VERSION 5.7 ;
  NOWIREEXTENSIONATPIN ON ;
  DIVIDERCHAR "/" ;
  BUSBITCHARS "[]" ;
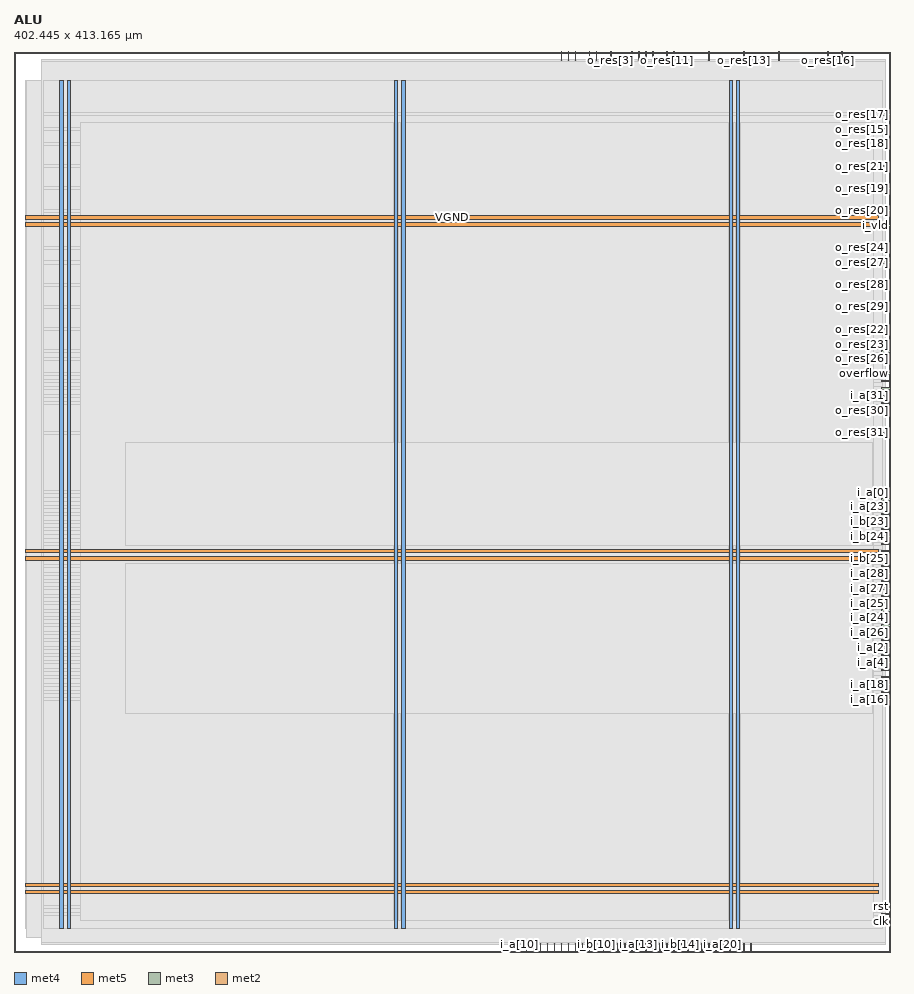
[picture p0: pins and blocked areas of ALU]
MACRO ALU
  CLASS BLOCK ;
  FOREIGN ALU ;
  ORIGIN 0.000 0.000 ;
  SIZE 402.445 BY 413.165 ;
  PIN VGND
    DIRECTION INOUT ;
    USE GROUND ;
    PORT
      LAYER met4 ;
        RECT 24.340 10.640 25.940 400.080 ;
    END
    PORT
      LAYER met4 ;
        RECT 177.940 10.640 179.540 400.080 ;
    END
    PORT
      LAYER met4 ;
        RECT 331.540 10.640 333.140 400.080 ;
    END
    PORT
      LAYER met5 ;
        RECT 5.280 30.030 396.760 31.630 ;
    END
    PORT
      LAYER met5 ;
        RECT 5.280 183.210 396.760 184.810 ;
    END
    PORT
      LAYER met5 ;
        RECT 5.280 336.390 396.760 337.990 ;
    END
  END VGND
  PIN VPWR
    DIRECTION INOUT ;
    USE POWER ;
    PORT
      LAYER met4 ;
        RECT 21.040 10.640 22.640 400.080 ;
    END
    PORT
      LAYER met4 ;
        RECT 174.640 10.640 176.240 400.080 ;
    END
    PORT
      LAYER met4 ;
        RECT 328.240 10.640 329.840 400.080 ;
    END
    PORT
      LAYER met5 ;
        RECT 5.280 26.730 396.760 28.330 ;
    END
    PORT
      LAYER met5 ;
        RECT 5.280 179.910 396.760 181.510 ;
    END
    PORT
      LAYER met5 ;
        RECT 5.280 333.090 396.760 334.690 ;
    END
  END VPWR
  PIN clk
    DIRECTION INPUT ;
    USE SIGNAL ;
    ANTENNAGATEAREA 0.852000 ;
    PORT
      LAYER met3 ;
        RECT 398.445 17.040 402.445 17.640 ;
    END
  END clk
  PIN i_a[0]
    DIRECTION INPUT ;
    USE SIGNAL ;
    ANTENNAGATEAREA 0.196500 ;
    PORT
      LAYER met3 ;
        RECT 398.445 210.840 402.445 211.440 ;
    END
  END i_a[0]
  PIN i_a[10]
    DIRECTION INPUT ;
    USE SIGNAL ;
    ANTENNAGATEAREA 0.196500 ;
    PORT
      LAYER met2 ;
        RECT 231.930 0.000 232.210 4.000 ;
    END
  END i_a[10]
  PIN i_a[11]
    DIRECTION INPUT ;
    USE SIGNAL ;
    ANTENNAGATEAREA 0.196500 ;
    PORT
      LAYER met2 ;
        RECT 251.250 0.000 251.530 4.000 ;
    END
  END i_a[11]
  PIN i_a[12]
    DIRECTION INPUT ;
    USE SIGNAL ;
    ANTENNAGATEAREA 0.196500 ;
    PORT
      LAYER met2 ;
        RECT 283.450 0.000 283.730 4.000 ;
    END
  END i_a[12]
  PIN i_a[13]
    DIRECTION INPUT ;
    USE SIGNAL ;
    ANTENNAGATEAREA 0.196500 ;
    PORT
      LAYER met2 ;
        RECT 286.670 0.000 286.950 4.000 ;
    END
  END i_a[13]
  PIN i_a[14]
    DIRECTION INPUT ;
    USE SIGNAL ;
    ANTENNAGATEAREA 0.196500 ;
    PORT
      LAYER met2 ;
        RECT 293.110 0.000 293.390 4.000 ;
    END
  END i_a[14]
  PIN i_a[15]
    DIRECTION INPUT ;
    USE SIGNAL ;
    ANTENNAGATEAREA 0.196500 ;
    PORT
      LAYER met2 ;
        RECT 289.890 0.000 290.170 4.000 ;
    END
  END i_a[15]
  PIN i_a[16]
    DIRECTION INPUT ;
    USE SIGNAL ;
    ANTENNAGATEAREA 0.196500 ;
    PORT
      LAYER met3 ;
        RECT 398.445 115.640 402.445 116.240 ;
    END
  END i_a[16]
  PIN i_a[17]
    DIRECTION INPUT ;
    USE SIGNAL ;
    ANTENNAGATEAREA 0.196500 ;
    PORT
      LAYER met3 ;
        RECT 398.445 132.640 402.445 133.240 ;
    END
  END i_a[17]
  PIN i_a[18]
    DIRECTION INPUT ;
    USE SIGNAL ;
    ANTENNAGATEAREA 0.196500 ;
    PORT
      LAYER met3 ;
        RECT 398.445 119.040 402.445 119.640 ;
    END
  END i_a[18]
  PIN i_a[19]
    DIRECTION INPUT ;
    USE SIGNAL ;
    ANTENNAGATEAREA 0.196500 ;
    PORT
      LAYER met3 ;
        RECT 398.445 122.440 402.445 123.040 ;
    END
  END i_a[19]
  PIN i_a[1]
    DIRECTION INPUT ;
    USE SIGNAL ;
    ANTENNAGATEAREA 0.196500 ;
    PORT
      LAYER met3 ;
        RECT 398.445 149.640 402.445 150.240 ;
    END
  END i_a[1]
  PIN i_a[20]
    DIRECTION INPUT ;
    USE SIGNAL ;
    ANTENNAGATEAREA 0.196500 ;
    PORT
      LAYER met2 ;
        RECT 325.310 0.000 325.590 4.000 ;
    END
  END i_a[20]
  PIN i_a[21]
    DIRECTION INPUT ;
    USE SIGNAL ;
    ANTENNAGATEAREA 0.196500 ;
    PORT
      LAYER met2 ;
        RECT 322.090 0.000 322.370 4.000 ;
    END
  END i_a[21]
  PIN i_a[22]
    DIRECTION INPUT ;
    USE SIGNAL ;
    ANTENNAGATEAREA 0.196500 ;
    PORT
      LAYER met2 ;
        RECT 312.430 0.000 312.710 4.000 ;
    END
  END i_a[22]
  PIN i_a[23]
    DIRECTION INPUT ;
    USE SIGNAL ;
    ANTENNAGATEAREA 0.196500 ;
    PORT
      LAYER met3 ;
        RECT 398.445 204.040 402.445 204.640 ;
    END
  END i_a[23]
  PIN i_a[24]
    DIRECTION INPUT ;
    USE SIGNAL ;
    ANTENNAGATEAREA 0.196500 ;
    PORT
      LAYER met3 ;
        RECT 398.445 153.040 402.445 153.640 ;
    END
  END i_a[24]
  PIN i_a[25]
    DIRECTION INPUT ;
    USE SIGNAL ;
    ANTENNAGATEAREA 0.196500 ;
    PORT
      LAYER met3 ;
        RECT 398.445 156.440 402.445 157.040 ;
    END
  END i_a[25]
  PIN i_a[26]
    DIRECTION INPUT ;
    USE SIGNAL ;
    ANTENNAGATEAREA 0.196500 ;
    PORT
      LAYER met3 ;
        RECT 398.445 146.240 402.445 146.840 ;
    END
  END i_a[26]
  PIN i_a[27]
    DIRECTION INPUT ;
    USE SIGNAL ;
    ANTENNAGATEAREA 0.196500 ;
    PORT
      LAYER met3 ;
        RECT 398.445 163.240 402.445 163.840 ;
    END
  END i_a[27]
  PIN i_a[28]
    DIRECTION INPUT ;
    USE SIGNAL ;
    ANTENNAGATEAREA 0.196500 ;
    PORT
      LAYER met3 ;
        RECT 398.445 173.440 402.445 174.040 ;
    END
  END i_a[28]
  PIN i_a[29]
    DIRECTION INPUT ;
    USE SIGNAL ;
    ANTENNAGATEAREA 0.196500 ;
    PORT
      LAYER met3 ;
        RECT 398.445 207.440 402.445 208.040 ;
    END
  END i_a[29]
  PIN i_a[2]
    DIRECTION INPUT ;
    USE SIGNAL ;
    ANTENNAGATEAREA 0.196500 ;
    PORT
      LAYER met3 ;
        RECT 398.445 142.840 402.445 143.440 ;
    END
  END i_a[2]
  PIN i_a[30]
    DIRECTION INPUT ;
    USE SIGNAL ;
    ANTENNAGATEAREA 0.196500 ;
    PORT
      LAYER met3 ;
        RECT 398.445 170.040 402.445 170.640 ;
    END
  END i_a[30]
  PIN i_a[31]
    DIRECTION INPUT ;
    USE SIGNAL ;
    ANTENNAGATEAREA 0.196500 ;
    PORT
      LAYER met3 ;
        RECT 398.445 255.040 402.445 255.640 ;
    END
  END i_a[31]
  PIN i_a[3]
    DIRECTION INPUT ;
    USE SIGNAL ;
    ANTENNAGATEAREA 0.196500 ;
    PORT
      LAYER met3 ;
        RECT 398.445 159.840 402.445 160.440 ;
    END
  END i_a[3]
  PIN i_a[4]
    DIRECTION INPUT ;
    USE SIGNAL ;
    ANTENNAGATEAREA 0.196500 ;
    PORT
      LAYER met3 ;
        RECT 398.445 136.040 402.445 136.640 ;
    END
  END i_a[4]
  PIN i_a[5]
    DIRECTION INPUT ;
    USE SIGNAL ;
    ANTENNAGATEAREA 0.196500 ;
    PORT
      LAYER met3 ;
        RECT 398.445 139.440 402.445 140.040 ;
    END
  END i_a[5]
  PIN i_a[6]
    DIRECTION INPUT ;
    USE SIGNAL ;
    ANTENNAGATEAREA 0.196500 ;
    PORT
      LAYER met3 ;
        RECT 398.445 125.840 402.445 126.440 ;
    END
  END i_a[6]
  PIN i_a[7]
    DIRECTION INPUT ;
    USE SIGNAL ;
    ANTENNAGATEAREA 0.196500 ;
    PORT
      LAYER met3 ;
        RECT 398.445 129.240 402.445 129.840 ;
    END
  END i_a[7]
  PIN i_a[8]
    DIRECTION INPUT ;
    USE SIGNAL ;
    ANTENNAGATEAREA 0.196500 ;
    PORT
      LAYER met2 ;
        RECT 244.810 0.000 245.090 4.000 ;
    END
  END i_a[8]
  PIN i_a[9]
    DIRECTION INPUT ;
    USE SIGNAL ;
    ANTENNAGATEAREA 0.196500 ;
    PORT
      LAYER met2 ;
        RECT 238.370 0.000 238.650 4.000 ;
    END
  END i_a[9]
  PIN i_b[0]
    DIRECTION INPUT ;
    USE SIGNAL ;
    ANTENNAGATEAREA 0.196500 ;
    PORT
      LAYER met2 ;
        RECT 257.690 0.000 257.970 4.000 ;
    END
  END i_b[0]
  PIN i_b[10]
    DIRECTION INPUT ;
    USE SIGNAL ;
    ANTENNAGATEAREA 0.196500 ;
    PORT
      LAYER met2 ;
        RECT 267.350 0.000 267.630 4.000 ;
    END
  END i_b[10]
  PIN i_b[11]
    DIRECTION INPUT ;
    USE SIGNAL ;
    ANTENNAGATEAREA 0.196500 ;
    PORT
      LAYER met2 ;
        RECT 241.590 0.000 241.870 4.000 ;
    END
  END i_b[11]
  PIN i_b[12]
    DIRECTION INPUT ;
    USE SIGNAL ;
    ANTENNAGATEAREA 0.196500 ;
    PORT
      LAYER met2 ;
        RECT 309.210 0.000 309.490 4.000 ;
    END
  END i_b[12]
  PIN i_b[13]
    DIRECTION INPUT ;
    USE SIGNAL ;
    ANTENNAGATEAREA 0.196500 ;
    PORT
      LAYER met2 ;
        RECT 315.650 0.000 315.930 4.000 ;
    END
  END i_b[13]
  PIN i_b[14]
    DIRECTION INPUT ;
    USE SIGNAL ;
    ANTENNAGATEAREA 0.196500 ;
    PORT
      LAYER met2 ;
        RECT 305.990 0.000 306.270 4.000 ;
    END
  END i_b[14]
  PIN i_b[15]
    DIRECTION INPUT ;
    USE SIGNAL ;
    ANTENNAGATEAREA 0.196500 ;
    PORT
      LAYER met2 ;
        RECT 318.870 0.000 319.150 4.000 ;
    END
  END i_b[15]
  PIN i_b[16]
    DIRECTION INPUT ;
    USE SIGNAL ;
    ANTENNAGATEAREA 0.196500 ;
    PORT
      LAYER met2 ;
        RECT 334.970 0.000 335.250 4.000 ;
    END
  END i_b[16]
  PIN i_b[17]
    DIRECTION INPUT ;
    USE SIGNAL ;
    ANTENNAGATEAREA 0.196500 ;
    PORT
      LAYER met2 ;
        RECT 338.190 0.000 338.470 4.000 ;
    END
  END i_b[17]
  PIN i_b[18]
    DIRECTION INPUT ;
    USE SIGNAL ;
    ANTENNAGATEAREA 0.196500 ;
    PORT
      LAYER met2 ;
        RECT 331.750 0.000 332.030 4.000 ;
    END
  END i_b[18]
  PIN i_b[19]
    DIRECTION INPUT ;
    USE SIGNAL ;
    ANTENNAGATEAREA 0.196500 ;
    PORT
      LAYER met2 ;
        RECT 328.530 0.000 328.810 4.000 ;
    END
  END i_b[19]
  PIN i_b[1]
    DIRECTION INPUT ;
    USE SIGNAL ;
    ANTENNAGATEAREA 0.196500 ;
    PORT
      LAYER met2 ;
        RECT 254.470 0.000 254.750 4.000 ;
    END
  END i_b[1]
  PIN i_b[20]
    DIRECTION INPUT ;
    USE SIGNAL ;
    ANTENNAGATEAREA 0.196500 ;
    PORT
      LAYER met2 ;
        RECT 299.550 0.000 299.830 4.000 ;
    END
  END i_b[20]
  PIN i_b[21]
    DIRECTION INPUT ;
    USE SIGNAL ;
    ANTENNAGATEAREA 0.196500 ;
    PORT
      LAYER met2 ;
        RECT 296.330 0.000 296.610 4.000 ;
    END
  END i_b[21]
  PIN i_b[22]
    DIRECTION INPUT ;
    USE SIGNAL ;
    ANTENNAGATEAREA 0.196500 ;
    PORT
      LAYER met2 ;
        RECT 302.770 0.000 303.050 4.000 ;
    END
  END i_b[22]
  PIN i_b[23]
    DIRECTION INPUT ;
    USE SIGNAL ;
    ANTENNAGATEAREA 0.196500 ;
    PORT
      LAYER met3 ;
        RECT 398.445 197.240 402.445 197.840 ;
    END
  END i_b[23]
  PIN i_b[24]
    DIRECTION INPUT ;
    USE SIGNAL ;
    ANTENNAGATEAREA 0.196500 ;
    PORT
      LAYER met3 ;
        RECT 398.445 193.840 402.445 194.440 ;
    END
  END i_b[24]
  PIN i_b[25]
    DIRECTION INPUT ;
    USE SIGNAL ;
    ANTENNAGATEAREA 0.196500 ;
    PORT
      LAYER met3 ;
        RECT 398.445 180.240 402.445 180.840 ;
    END
  END i_b[25]
  PIN i_b[26]
    DIRECTION INPUT ;
    USE SIGNAL ;
    ANTENNAGATEAREA 0.196500 ;
    PORT
      LAYER met3 ;
        RECT 398.445 166.640 402.445 167.240 ;
    END
  END i_b[26]
  PIN i_b[27]
    DIRECTION INPUT ;
    USE SIGNAL ;
    ANTENNAGATEAREA 0.196500 ;
    PORT
      LAYER met3 ;
        RECT 398.445 187.040 402.445 187.640 ;
    END
  END i_b[27]
  PIN i_b[28]
    DIRECTION INPUT ;
    USE SIGNAL ;
    ANTENNAGATEAREA 0.196500 ;
    PORT
      LAYER met3 ;
        RECT 398.445 176.840 402.445 177.440 ;
    END
  END i_b[28]
  PIN i_b[29]
    DIRECTION INPUT ;
    USE SIGNAL ;
    ANTENNAGATEAREA 0.196500 ;
    PORT
      LAYER met3 ;
        RECT 398.445 183.640 402.445 184.240 ;
    END
  END i_b[29]
  PIN i_b[2]
    DIRECTION INPUT ;
    USE SIGNAL ;
    ANTENNAGATEAREA 0.196500 ;
    PORT
      LAYER met2 ;
        RECT 248.030 0.000 248.310 4.000 ;
    END
  END i_b[2]
  PIN i_b[30]
    DIRECTION INPUT ;
    USE SIGNAL ;
    ANTENNAGATEAREA 0.196500 ;
    PORT
      LAYER met3 ;
        RECT 398.445 190.440 402.445 191.040 ;
    END
  END i_b[30]
  PIN i_b[31]
    DIRECTION INPUT ;
    USE SIGNAL ;
    ANTENNAGATEAREA 0.196500 ;
    PORT
      LAYER met3 ;
        RECT 398.445 261.840 402.445 262.440 ;
    END
  END i_b[31]
  PIN i_b[3]
    DIRECTION INPUT ;
    USE SIGNAL ;
    ANTENNAGATEAREA 0.196500 ;
    PORT
      LAYER met2 ;
        RECT 264.130 0.000 264.410 4.000 ;
    END
  END i_b[3]
  PIN i_b[4]
    DIRECTION INPUT ;
    USE SIGNAL ;
    ANTENNAGATEAREA 0.196500 ;
    PORT
      LAYER met2 ;
        RECT 235.150 0.000 235.430 4.000 ;
    END
  END i_b[4]
  PIN i_b[5]
    DIRECTION INPUT ;
    USE SIGNAL ;
    ANTENNAGATEAREA 0.196500 ;
    PORT
      LAYER met2 ;
        RECT 270.570 0.000 270.850 4.000 ;
    END
  END i_b[5]
  PIN i_b[6]
    DIRECTION INPUT ;
    USE SIGNAL ;
    ANTENNAGATEAREA 0.196500 ;
    PORT
      LAYER met2 ;
        RECT 280.230 0.000 280.510 4.000 ;
    END
  END i_b[6]
  PIN i_b[7]
    DIRECTION INPUT ;
    USE SIGNAL ;
    ANTENNAGATEAREA 0.196500 ;
    PORT
      LAYER met2 ;
        RECT 277.010 0.000 277.290 4.000 ;
    END
  END i_b[7]
  PIN i_b[8]
    DIRECTION INPUT ;
    USE SIGNAL ;
    ANTENNAGATEAREA 0.196500 ;
    PORT
      LAYER met2 ;
        RECT 260.910 0.000 261.190 4.000 ;
    END
  END i_b[8]
  PIN i_b[9]
    DIRECTION INPUT ;
    USE SIGNAL ;
    ANTENNAGATEAREA 0.196500 ;
    PORT
      LAYER met2 ;
        RECT 273.790 0.000 274.070 4.000 ;
    END
  END i_b[9]
  PIN i_vld
    DIRECTION INPUT ;
    USE SIGNAL ;
    ANTENNAGATEAREA 0.196500 ;
    PORT
      LAYER met3 ;
        RECT 398.445 333.240 402.445 333.840 ;
    END
  END i_vld
  PIN o_res[0]
    DIRECTION OUTPUT ;
    USE SIGNAL ;
    ANTENNADIFFAREA 0.445500 ;
    PORT
      LAYER met2 ;
        RECT 254.470 409.165 254.750 413.165 ;
    END
  END o_res[0]
  PIN o_res[10]
    DIRECTION OUTPUT ;
    USE SIGNAL ;
    ANTENNADIFFAREA 0.445500 ;
    PORT
      LAYER met2 ;
        RECT 302.770 409.165 303.050 413.165 ;
    END
  END o_res[10]
  PIN o_res[11]
    DIRECTION OUTPUT ;
    USE SIGNAL ;
    ANTENNADIFFAREA 0.445500 ;
    PORT
      LAYER met2 ;
        RECT 299.550 409.165 299.830 413.165 ;
    END
  END o_res[11]
  PIN o_res[12]
    DIRECTION OUTPUT ;
    USE SIGNAL ;
    ANTENNADIFFAREA 0.445500 ;
    PORT
      LAYER met2 ;
        RECT 318.870 409.165 319.150 413.165 ;
    END
  END o_res[12]
  PIN o_res[13]
    DIRECTION OUTPUT ;
    USE SIGNAL ;
    ANTENNADIFFAREA 0.445500 ;
    PORT
      LAYER met2 ;
        RECT 334.970 409.165 335.250 413.165 ;
    END
  END o_res[13]
  PIN o_res[14]
    DIRECTION OUTPUT ;
    USE SIGNAL ;
    ANTENNADIFFAREA 0.445500 ;
    PORT
      LAYER met2 ;
        RECT 351.070 409.165 351.350 413.165 ;
    END
  END o_res[14]
  PIN o_res[15]
    DIRECTION OUTPUT ;
    USE SIGNAL ;
    ANTENNADIFFAREA 0.445500 ;
    PORT
      LAYER met3 ;
        RECT 398.445 377.440 402.445 378.040 ;
    END
  END o_res[15]
  PIN o_res[16]
    DIRECTION OUTPUT ;
    USE SIGNAL ;
    ANTENNADIFFAREA 0.445500 ;
    PORT
      LAYER met2 ;
        RECT 373.610 409.165 373.890 413.165 ;
    END
  END o_res[16]
  PIN o_res[17]
    DIRECTION OUTPUT ;
    USE SIGNAL ;
    ANTENNADIFFAREA 0.445500 ;
    PORT
      LAYER met3 ;
        RECT 398.445 384.240 402.445 384.840 ;
    END
  END o_res[17]
  PIN o_res[18]
    DIRECTION OUTPUT ;
    USE SIGNAL ;
    ANTENNADIFFAREA 0.445500 ;
    PORT
      LAYER met3 ;
        RECT 398.445 370.640 402.445 371.240 ;
    END
  END o_res[18]
  PIN o_res[19]
    DIRECTION OUTPUT ;
    USE SIGNAL ;
    ANTENNADIFFAREA 0.445500 ;
    PORT
      LAYER met3 ;
        RECT 398.445 350.240 402.445 350.840 ;
    END
  END o_res[19]
  PIN o_res[1]
    DIRECTION OUTPUT ;
    USE SIGNAL ;
    ANTENNADIFFAREA 0.445500 ;
    PORT
      LAYER met2 ;
        RECT 251.250 409.165 251.530 413.165 ;
    END
  END o_res[1]
  PIN o_res[20]
    DIRECTION OUTPUT ;
    USE SIGNAL ;
    ANTENNADIFFAREA 0.445500 ;
    PORT
      LAYER met3 ;
        RECT 398.445 340.040 402.445 340.640 ;
    END
  END o_res[20]
  PIN o_res[21]
    DIRECTION OUTPUT ;
    USE SIGNAL ;
    ANTENNADIFFAREA 0.445500 ;
    PORT
      LAYER met3 ;
        RECT 398.445 360.440 402.445 361.040 ;
    END
  END o_res[21]
  PIN o_res[22]
    DIRECTION OUTPUT ;
    USE SIGNAL ;
    ANTENNADIFFAREA 0.445500 ;
    PORT
      LAYER met3 ;
        RECT 398.445 285.640 402.445 286.240 ;
    END
  END o_res[22]
  PIN o_res[23]
    DIRECTION OUTPUT ;
    USE SIGNAL ;
    ANTENNADIFFAREA 0.445500 ;
    PORT
      LAYER met3 ;
        RECT 398.445 275.440 402.445 276.040 ;
    END
  END o_res[23]
  PIN o_res[24]
    DIRECTION OUTPUT ;
    USE SIGNAL ;
    ANTENNADIFFAREA 0.445500 ;
    PORT
      LAYER met3 ;
        RECT 398.445 323.040 402.445 323.640 ;
    END
  END o_res[24]
  PIN o_res[25]
    DIRECTION OUTPUT ;
    USE SIGNAL ;
    ANTENNADIFFAREA 0.445500 ;
    PORT
      LAYER met3 ;
        RECT 398.445 258.440 402.445 259.040 ;
    END
  END o_res[25]
  PIN o_res[26]
    DIRECTION OUTPUT ;
    USE SIGNAL ;
    ANTENNADIFFAREA 0.445500 ;
    PORT
      LAYER met3 ;
        RECT 398.445 272.040 402.445 272.640 ;
    END
  END o_res[26]
  PIN o_res[27]
    DIRECTION OUTPUT ;
    USE SIGNAL ;
    ANTENNADIFFAREA 0.445500 ;
    PORT
      LAYER met3 ;
        RECT 398.445 316.240 402.445 316.840 ;
    END
  END o_res[27]
  PIN o_res[28]
    DIRECTION OUTPUT ;
    USE SIGNAL ;
    ANTENNADIFFAREA 0.445500 ;
    PORT
      LAYER met3 ;
        RECT 398.445 306.040 402.445 306.640 ;
    END
  END o_res[28]
  PIN o_res[29]
    DIRECTION OUTPUT ;
    USE SIGNAL ;
    ANTENNADIFFAREA 0.445500 ;
    PORT
      LAYER met3 ;
        RECT 398.445 295.840 402.445 296.440 ;
    END
  END o_res[29]
  PIN o_res[2]
    DIRECTION OUTPUT ;
    USE SIGNAL ;
    ANTENNADIFFAREA 0.445500 ;
    PORT
      LAYER met2 ;
        RECT 257.690 409.165 257.970 413.165 ;
    END
  END o_res[2]
  PIN o_res[30]
    DIRECTION OUTPUT ;
    USE SIGNAL ;
    ANTENNADIFFAREA 0.445500 ;
    PORT
      LAYER met3 ;
        RECT 398.445 251.640 402.445 252.240 ;
    END
  END o_res[30]
  PIN o_res[31]
    DIRECTION OUTPUT ;
    USE SIGNAL ;
    ANTENNADIFFAREA 0.445500 ;
    PORT
      LAYER met3 ;
        RECT 398.445 238.040 402.445 238.640 ;
    END
  END o_res[31]
  PIN o_res[3]
    DIRECTION OUTPUT ;
    USE SIGNAL ;
    ANTENNADIFFAREA 0.445500 ;
    PORT
      LAYER met2 ;
        RECT 273.790 409.165 274.070 413.165 ;
    END
  END o_res[3]
  PIN o_res[4]
    DIRECTION OUTPUT ;
    USE SIGNAL ;
    ANTENNADIFFAREA 0.445500 ;
    PORT
      LAYER met2 ;
        RECT 264.130 409.165 264.410 413.165 ;
    END
  END o_res[4]
  PIN o_res[5]
    DIRECTION OUTPUT ;
    USE SIGNAL ;
    ANTENNADIFFAREA 0.445500 ;
    PORT
      LAYER met2 ;
        RECT 293.110 409.165 293.390 413.165 ;
    END
  END o_res[5]
  PIN o_res[6]
    DIRECTION OUTPUT ;
    USE SIGNAL ;
    ANTENNADIFFAREA 0.445500 ;
    PORT
      LAYER met2 ;
        RECT 289.890 409.165 290.170 413.165 ;
    END
  END o_res[6]
  PIN o_res[7]
    DIRECTION OUTPUT ;
    USE SIGNAL ;
    ANTENNADIFFAREA 0.445500 ;
    PORT
      LAYER met2 ;
        RECT 267.350 409.165 267.630 413.165 ;
    END
  END o_res[7]
  PIN o_res[8]
    DIRECTION OUTPUT ;
    USE SIGNAL ;
    ANTENNADIFFAREA 0.445500 ;
    PORT
      LAYER met2 ;
        RECT 286.670 409.165 286.950 413.165 ;
    END
  END o_res[8]
  PIN o_res[9]
    DIRECTION OUTPUT ;
    USE SIGNAL ;
    ANTENNADIFFAREA 0.445500 ;
    PORT
      LAYER met2 ;
        RECT 283.450 409.165 283.730 413.165 ;
    END
  END o_res[9]
  PIN o_res_vld
    DIRECTION OUTPUT ;
    USE SIGNAL ;
    ANTENNADIFFAREA 0.445500 ;
    PORT
      LAYER met3 ;
        RECT 398.445 200.640 402.445 201.240 ;
    END
  END o_res_vld
  PIN opcode
    DIRECTION INPUT ;
    USE SIGNAL ;
    ANTENNAGATEAREA 0.196500 ;
    PORT
      LAYER met2 ;
        RECT 380.050 409.165 380.330 413.165 ;
    END
  END opcode
  PIN overflow
    DIRECTION OUTPUT ;
    USE SIGNAL ;
    ANTENNADIFFAREA 0.445500 ;
    PORT
      LAYER met3 ;
        RECT 398.445 265.240 402.445 265.840 ;
    END
  END overflow
  PIN rst
    DIRECTION INPUT ;
    USE SIGNAL ;
    ANTENNAGATEAREA 0.196500 ;
    PORT
      LAYER met3 ;
        RECT 398.445 20.440 402.445 21.040 ;
    END
  END rst
  OBS
      LAYER nwell ;
        RECT 5.330 10.795 396.710 400.030 ;
      LAYER li1 ;
        RECT 5.520 10.795 396.520 399.925 ;
      LAYER met1 ;
        RECT 5.520 6.840 400.130 400.080 ;
      LAYER met2 ;
        RECT 12.520 408.885 250.970 409.770 ;
        RECT 251.810 408.885 254.190 409.770 ;
        RECT 255.030 408.885 257.410 409.770 ;
        RECT 258.250 408.885 263.850 409.770 ;
        RECT 264.690 408.885 267.070 409.770 ;
        RECT 267.910 408.885 273.510 409.770 ;
        RECT 274.350 408.885 283.170 409.770 ;
        RECT 284.010 408.885 286.390 409.770 ;
        RECT 287.230 408.885 289.610 409.770 ;
        RECT 290.450 408.885 292.830 409.770 ;
        RECT 293.670 408.885 299.270 409.770 ;
        RECT 300.110 408.885 302.490 409.770 ;
        RECT 303.330 408.885 318.590 409.770 ;
        RECT 319.430 408.885 334.690 409.770 ;
        RECT 335.530 408.885 350.790 409.770 ;
        RECT 351.630 408.885 373.330 409.770 ;
        RECT 374.170 408.885 379.770 409.770 ;
        RECT 380.610 408.885 400.100 409.770 ;
        RECT 12.520 4.280 400.100 408.885 ;
        RECT 12.520 3.670 231.650 4.280 ;
        RECT 232.490 3.670 234.870 4.280 ;
        RECT 235.710 3.670 238.090 4.280 ;
        RECT 238.930 3.670 241.310 4.280 ;
        RECT 242.150 3.670 244.530 4.280 ;
        RECT 245.370 3.670 247.750 4.280 ;
        RECT 248.590 3.670 250.970 4.280 ;
        RECT 251.810 3.670 254.190 4.280 ;
        RECT 255.030 3.670 257.410 4.280 ;
        RECT 258.250 3.670 260.630 4.280 ;
        RECT 261.470 3.670 263.850 4.280 ;
        RECT 264.690 3.670 267.070 4.280 ;
        RECT 267.910 3.670 270.290 4.280 ;
        RECT 271.130 3.670 273.510 4.280 ;
        RECT 274.350 3.670 276.730 4.280 ;
        RECT 277.570 3.670 279.950 4.280 ;
        RECT 280.790 3.670 283.170 4.280 ;
        RECT 284.010 3.670 286.390 4.280 ;
        RECT 287.230 3.670 289.610 4.280 ;
        RECT 290.450 3.670 292.830 4.280 ;
        RECT 293.670 3.670 296.050 4.280 ;
        RECT 296.890 3.670 299.270 4.280 ;
        RECT 300.110 3.670 302.490 4.280 ;
        RECT 303.330 3.670 305.710 4.280 ;
        RECT 306.550 3.670 308.930 4.280 ;
        RECT 309.770 3.670 312.150 4.280 ;
        RECT 312.990 3.670 315.370 4.280 ;
        RECT 316.210 3.670 318.590 4.280 ;
        RECT 319.430 3.670 321.810 4.280 ;
        RECT 322.650 3.670 325.030 4.280 ;
        RECT 325.870 3.670 328.250 4.280 ;
        RECT 329.090 3.670 331.470 4.280 ;
        RECT 332.310 3.670 334.690 4.280 ;
        RECT 335.530 3.670 337.910 4.280 ;
        RECT 338.750 3.670 400.100 4.280 ;
      LAYER met3 ;
        RECT 13.405 385.240 398.755 400.005 ;
        RECT 13.405 383.840 398.045 385.240 ;
        RECT 13.405 378.440 398.755 383.840 ;
        RECT 13.405 377.040 398.045 378.440 ;
        RECT 13.405 371.640 398.755 377.040 ;
        RECT 13.405 370.240 398.045 371.640 ;
        RECT 13.405 361.440 398.755 370.240 ;
        RECT 13.405 360.040 398.045 361.440 ;
        RECT 13.405 351.240 398.755 360.040 ;
        RECT 13.405 349.840 398.045 351.240 ;
        RECT 13.405 341.040 398.755 349.840 ;
        RECT 13.405 339.640 398.045 341.040 ;
        RECT 13.405 334.240 398.755 339.640 ;
        RECT 13.405 332.840 398.045 334.240 ;
        RECT 13.405 324.040 398.755 332.840 ;
        RECT 13.405 322.640 398.045 324.040 ;
        RECT 13.405 317.240 398.755 322.640 ;
        RECT 13.405 315.840 398.045 317.240 ;
        RECT 13.405 307.040 398.755 315.840 ;
        RECT 13.405 305.640 398.045 307.040 ;
        RECT 13.405 296.840 398.755 305.640 ;
        RECT 13.405 295.440 398.045 296.840 ;
        RECT 13.405 286.640 398.755 295.440 ;
        RECT 13.405 285.240 398.045 286.640 ;
        RECT 13.405 276.440 398.755 285.240 ;
        RECT 13.405 275.040 398.045 276.440 ;
        RECT 13.405 273.040 398.755 275.040 ;
        RECT 13.405 271.640 398.045 273.040 ;
        RECT 13.405 266.240 398.755 271.640 ;
        RECT 13.405 264.840 398.045 266.240 ;
        RECT 13.405 262.840 398.755 264.840 ;
        RECT 13.405 261.440 398.045 262.840 ;
        RECT 13.405 259.440 398.755 261.440 ;
        RECT 13.405 258.040 398.045 259.440 ;
        RECT 13.405 256.040 398.755 258.040 ;
        RECT 13.405 254.640 398.045 256.040 ;
        RECT 13.405 252.640 398.755 254.640 ;
        RECT 13.405 251.240 398.045 252.640 ;
        RECT 13.405 239.040 398.755 251.240 ;
        RECT 13.405 237.640 398.045 239.040 ;
        RECT 13.405 211.840 398.755 237.640 ;
        RECT 13.405 210.440 398.045 211.840 ;
        RECT 13.405 208.440 398.755 210.440 ;
        RECT 13.405 207.040 398.045 208.440 ;
        RECT 13.405 205.040 398.755 207.040 ;
        RECT 13.405 203.640 398.045 205.040 ;
        RECT 13.405 201.640 398.755 203.640 ;
        RECT 13.405 200.240 398.045 201.640 ;
        RECT 13.405 198.240 398.755 200.240 ;
        RECT 13.405 196.840 398.045 198.240 ;
        RECT 13.405 194.840 398.755 196.840 ;
        RECT 13.405 193.440 398.045 194.840 ;
        RECT 13.405 191.440 398.755 193.440 ;
        RECT 13.405 190.040 398.045 191.440 ;
        RECT 13.405 188.040 398.755 190.040 ;
        RECT 13.405 186.640 398.045 188.040 ;
        RECT 13.405 184.640 398.755 186.640 ;
        RECT 13.405 183.240 398.045 184.640 ;
        RECT 13.405 181.240 398.755 183.240 ;
        RECT 13.405 179.840 398.045 181.240 ;
        RECT 13.405 177.840 398.755 179.840 ;
        RECT 13.405 176.440 398.045 177.840 ;
        RECT 13.405 174.440 398.755 176.440 ;
        RECT 13.405 173.040 398.045 174.440 ;
        RECT 13.405 171.040 398.755 173.040 ;
        RECT 13.405 169.640 398.045 171.040 ;
        RECT 13.405 167.640 398.755 169.640 ;
        RECT 13.405 166.240 398.045 167.640 ;
        RECT 13.405 164.240 398.755 166.240 ;
        RECT 13.405 162.840 398.045 164.240 ;
        RECT 13.405 160.840 398.755 162.840 ;
        RECT 13.405 159.440 398.045 160.840 ;
        RECT 13.405 157.440 398.755 159.440 ;
        RECT 13.405 156.040 398.045 157.440 ;
        RECT 13.405 154.040 398.755 156.040 ;
        RECT 13.405 152.640 398.045 154.040 ;
        RECT 13.405 150.640 398.755 152.640 ;
        RECT 13.405 149.240 398.045 150.640 ;
        RECT 13.405 147.240 398.755 149.240 ;
        RECT 13.405 145.840 398.045 147.240 ;
        RECT 13.405 143.840 398.755 145.840 ;
        RECT 13.405 142.440 398.045 143.840 ;
        RECT 13.405 140.440 398.755 142.440 ;
        RECT 13.405 139.040 398.045 140.440 ;
        RECT 13.405 137.040 398.755 139.040 ;
        RECT 13.405 135.640 398.045 137.040 ;
        RECT 13.405 133.640 398.755 135.640 ;
        RECT 13.405 132.240 398.045 133.640 ;
        RECT 13.405 130.240 398.755 132.240 ;
        RECT 13.405 128.840 398.045 130.240 ;
        RECT 13.405 126.840 398.755 128.840 ;
        RECT 13.405 125.440 398.045 126.840 ;
        RECT 13.405 123.440 398.755 125.440 ;
        RECT 13.405 122.040 398.045 123.440 ;
        RECT 13.405 120.040 398.755 122.040 ;
        RECT 13.405 118.640 398.045 120.040 ;
        RECT 13.405 116.640 398.755 118.640 ;
        RECT 13.405 115.240 398.045 116.640 ;
        RECT 13.405 21.440 398.755 115.240 ;
        RECT 13.405 20.040 398.045 21.440 ;
        RECT 13.405 18.040 398.755 20.040 ;
        RECT 13.405 16.640 398.045 18.040 ;
        RECT 13.405 10.715 398.755 16.640 ;
      LAYER met4 ;
        RECT 30.655 14.455 174.240 380.625 ;
        RECT 176.640 14.455 177.540 380.625 ;
        RECT 179.940 14.455 327.840 380.625 ;
        RECT 330.240 14.455 331.140 380.625 ;
        RECT 333.540 14.455 394.385 380.625 ;
      LAYER met5 ;
        RECT 51.180 186.410 394.100 233.700 ;
        RECT 51.180 109.700 394.100 178.310 ;
  END
END ALU
END LIBRARY

